VERSION 5.7 ;
  NOWIREEXTENSIONATPIN ON ;
  DIVIDERCHAR "/" ;
  BUSBITCHARS "[]" ;
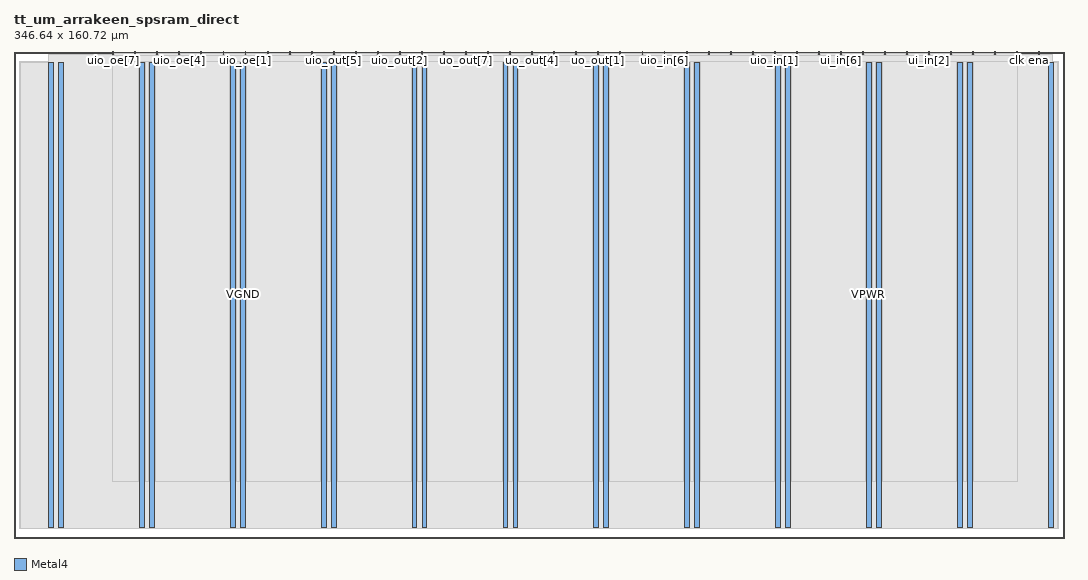
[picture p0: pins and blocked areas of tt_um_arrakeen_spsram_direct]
MACRO tt_um_arrakeen_spsram_direct
  CLASS BLOCK ;
  FOREIGN tt_um_arrakeen_spsram_direct ;
  ORIGIN 0.000 0.000 ;
  SIZE 346.640 BY 160.720 ;
  PIN VGND
    DIRECTION INOUT ;
    USE GROUND ;
    PORT
      LAYER Metal4 ;
        RECT 14.740 3.620 16.340 157.100 ;
    END
    PORT
      LAYER Metal4 ;
        RECT 44.740 3.620 46.340 157.100 ;
    END
    PORT
      LAYER Metal4 ;
        RECT 74.740 3.620 76.340 157.100 ;
    END
    PORT
      LAYER Metal4 ;
        RECT 104.740 3.620 106.340 157.100 ;
    END
    PORT
      LAYER Metal4 ;
        RECT 134.740 3.620 136.340 157.100 ;
    END
    PORT
      LAYER Metal4 ;
        RECT 164.740 3.620 166.340 157.100 ;
    END
    PORT
      LAYER Metal4 ;
        RECT 194.740 3.620 196.340 157.100 ;
    END
    PORT
      LAYER Metal4 ;
        RECT 224.740 3.620 226.340 157.100 ;
    END
    PORT
      LAYER Metal4 ;
        RECT 254.740 3.620 256.340 157.100 ;
    END
    PORT
      LAYER Metal4 ;
        RECT 284.740 3.620 286.340 157.100 ;
    END
    PORT
      LAYER Metal4 ;
        RECT 314.740 3.620 316.340 157.100 ;
    END
  END VGND
  PIN VPWR
    DIRECTION INOUT ;
    USE POWER ;
    PORT
      LAYER Metal4 ;
        RECT 11.440 3.620 13.040 157.100 ;
    END
    PORT
      LAYER Metal4 ;
        RECT 41.440 3.620 43.040 157.100 ;
    END
    PORT
      LAYER Metal4 ;
        RECT 71.440 3.620 73.040 157.100 ;
    END
    PORT
      LAYER Metal4 ;
        RECT 101.440 3.620 103.040 157.100 ;
    END
    PORT
      LAYER Metal4 ;
        RECT 131.440 3.620 133.040 157.100 ;
    END
    PORT
      LAYER Metal4 ;
        RECT 161.440 3.620 163.040 157.100 ;
    END
    PORT
      LAYER Metal4 ;
        RECT 191.440 3.620 193.040 157.100 ;
    END
    PORT
      LAYER Metal4 ;
        RECT 221.440 3.620 223.040 157.100 ;
    END
    PORT
      LAYER Metal4 ;
        RECT 251.440 3.620 253.040 157.100 ;
    END
    PORT
      LAYER Metal4 ;
        RECT 281.440 3.620 283.040 157.100 ;
    END
    PORT
      LAYER Metal4 ;
        RECT 311.440 3.620 313.040 157.100 ;
    END
    PORT
      LAYER Metal4 ;
        RECT 341.440 3.620 343.040 157.100 ;
    END
  END VPWR
  PIN clk
    DIRECTION INPUT ;
    USE SIGNAL ;
    ANTENNAGATEAREA 1.971200 ;
    ANTENNADIFFAREA 0.410400 ;
    PORT
      LAYER Metal4 ;
        RECT 331.090 159.720 331.390 160.720 ;
    END
  END clk
  PIN ena
    DIRECTION INPUT ;
    USE SIGNAL ;
    PORT
      LAYER Metal4 ;
        RECT 338.370 159.720 338.670 160.720 ;
    END
  END ena
  PIN rst_n
    DIRECTION INPUT ;
    USE SIGNAL ;
    PORT
      LAYER Metal4 ;
        RECT 323.810 159.720 324.110 160.720 ;
    END
  END rst_n
  PIN ui_in[0]
    DIRECTION INPUT ;
    USE SIGNAL ;
    ANTENNAGATEAREA 0.638400 ;
    ANTENNADIFFAREA 0.410400 ;
    PORT
      LAYER Metal4 ;
        RECT 316.530 159.720 316.830 160.720 ;
    END
  END ui_in[0]
  PIN ui_in[1]
    DIRECTION INPUT ;
    USE SIGNAL ;
    ANTENNAGATEAREA 0.638400 ;
    ANTENNADIFFAREA 0.410400 ;
    PORT
      LAYER Metal4 ;
        RECT 309.250 159.720 309.550 160.720 ;
    END
  END ui_in[1]
  PIN ui_in[2]
    DIRECTION INPUT ;
    USE SIGNAL ;
    ANTENNAGATEAREA 0.638400 ;
    ANTENNADIFFAREA 0.410400 ;
    PORT
      LAYER Metal4 ;
        RECT 301.970 159.720 302.270 160.720 ;
    END
  END ui_in[2]
  PIN ui_in[3]
    DIRECTION INPUT ;
    USE SIGNAL ;
    ANTENNAGATEAREA 0.638400 ;
    ANTENNADIFFAREA 0.410400 ;
    PORT
      LAYER Metal4 ;
        RECT 294.690 159.720 294.990 160.720 ;
    END
  END ui_in[3]
  PIN ui_in[4]
    DIRECTION INPUT ;
    USE SIGNAL ;
    ANTENNAGATEAREA 0.638400 ;
    ANTENNADIFFAREA 0.410400 ;
    PORT
      LAYER Metal4 ;
        RECT 287.410 159.720 287.710 160.720 ;
    END
  END ui_in[4]
  PIN ui_in[5]
    DIRECTION INPUT ;
    USE SIGNAL ;
    ANTENNAGATEAREA 0.638400 ;
    ANTENNADIFFAREA 0.410400 ;
    PORT
      LAYER Metal4 ;
        RECT 280.130 159.720 280.430 160.720 ;
    END
  END ui_in[5]
  PIN ui_in[6]
    DIRECTION INPUT ;
    USE SIGNAL ;
    ANTENNAGATEAREA 0.638400 ;
    ANTENNADIFFAREA 0.410400 ;
    PORT
      LAYER Metal4 ;
        RECT 272.850 159.720 273.150 160.720 ;
    END
  END ui_in[6]
  PIN ui_in[7]
    DIRECTION INPUT ;
    USE SIGNAL ;
    ANTENNAGATEAREA 0.492800 ;
    ANTENNADIFFAREA 0.410400 ;
    PORT
      LAYER Metal4 ;
        RECT 265.570 159.720 265.870 160.720 ;
    END
  END ui_in[7]
  PIN uio_in[0]
    DIRECTION INPUT ;
    USE SIGNAL ;
    ANTENNAGATEAREA 0.492800 ;
    ANTENNADIFFAREA 0.410400 ;
    PORT
      LAYER Metal4 ;
        RECT 258.290 159.720 258.590 160.720 ;
    END
  END uio_in[0]
  PIN uio_in[1]
    DIRECTION INPUT ;
    USE SIGNAL ;
    ANTENNAGATEAREA 0.492800 ;
    ANTENNADIFFAREA 0.410400 ;
    PORT
      LAYER Metal4 ;
        RECT 251.010 159.720 251.310 160.720 ;
    END
  END uio_in[1]
  PIN uio_in[2]
    DIRECTION INPUT ;
    USE SIGNAL ;
    ANTENNAGATEAREA 0.492800 ;
    ANTENNADIFFAREA 0.410400 ;
    PORT
      LAYER Metal4 ;
        RECT 243.730 159.720 244.030 160.720 ;
    END
  END uio_in[2]
  PIN uio_in[3]
    DIRECTION INPUT ;
    USE SIGNAL ;
    ANTENNAGATEAREA 0.492800 ;
    ANTENNADIFFAREA 0.410400 ;
    PORT
      LAYER Metal4 ;
        RECT 236.450 159.720 236.750 160.720 ;
    END
  END uio_in[3]
  PIN uio_in[4]
    DIRECTION INPUT ;
    USE SIGNAL ;
    ANTENNAGATEAREA 0.492800 ;
    ANTENNADIFFAREA 0.410400 ;
    PORT
      LAYER Metal4 ;
        RECT 229.170 159.720 229.470 160.720 ;
    END
  END uio_in[4]
  PIN uio_in[5]
    DIRECTION INPUT ;
    USE SIGNAL ;
    ANTENNAGATEAREA 0.492800 ;
    ANTENNADIFFAREA 0.410400 ;
    PORT
      LAYER Metal4 ;
        RECT 221.890 159.720 222.190 160.720 ;
    END
  END uio_in[5]
  PIN uio_in[6]
    DIRECTION INPUT ;
    USE SIGNAL ;
    ANTENNAGATEAREA 0.492800 ;
    ANTENNADIFFAREA 0.410400 ;
    PORT
      LAYER Metal4 ;
        RECT 214.610 159.720 214.910 160.720 ;
    END
  END uio_in[6]
  PIN uio_in[7]
    DIRECTION INPUT ;
    USE SIGNAL ;
    ANTENNAGATEAREA 0.492800 ;
    ANTENNADIFFAREA 0.410400 ;
    PORT
      LAYER Metal4 ;
        RECT 207.330 159.720 207.630 160.720 ;
    END
  END uio_in[7]
  PIN uio_oe[0]
    DIRECTION OUTPUT ;
    USE SIGNAL ;
    ANTENNADIFFAREA 0.360800 ;
    PORT
      LAYER Metal4 ;
        RECT 83.570 159.720 83.870 160.720 ;
    END
  END uio_oe[0]
  PIN uio_oe[1]
    DIRECTION OUTPUT ;
    USE SIGNAL ;
    ANTENNADIFFAREA 0.360800 ;
    PORT
      LAYER Metal4 ;
        RECT 76.290 159.720 76.590 160.720 ;
    END
  END uio_oe[1]
  PIN uio_oe[2]
    DIRECTION OUTPUT ;
    USE SIGNAL ;
    ANTENNADIFFAREA 0.360800 ;
    PORT
      LAYER Metal4 ;
        RECT 69.010 159.720 69.310 160.720 ;
    END
  END uio_oe[2]
  PIN uio_oe[3]
    DIRECTION OUTPUT ;
    USE SIGNAL ;
    ANTENNADIFFAREA 0.360800 ;
    PORT
      LAYER Metal4 ;
        RECT 61.730 159.720 62.030 160.720 ;
    END
  END uio_oe[3]
  PIN uio_oe[4]
    DIRECTION OUTPUT ;
    USE SIGNAL ;
    ANTENNADIFFAREA 0.360800 ;
    PORT
      LAYER Metal4 ;
        RECT 54.450 159.720 54.750 160.720 ;
    END
  END uio_oe[4]
  PIN uio_oe[5]
    DIRECTION OUTPUT ;
    USE SIGNAL ;
    ANTENNADIFFAREA 0.360800 ;
    PORT
      LAYER Metal4 ;
        RECT 47.170 159.720 47.470 160.720 ;
    END
  END uio_oe[5]
  PIN uio_oe[6]
    DIRECTION OUTPUT ;
    USE SIGNAL ;
    ANTENNADIFFAREA 0.360800 ;
    PORT
      LAYER Metal4 ;
        RECT 39.890 159.720 40.190 160.720 ;
    END
  END uio_oe[6]
  PIN uio_oe[7]
    DIRECTION OUTPUT ;
    USE SIGNAL ;
    ANTENNADIFFAREA 0.360800 ;
    PORT
      LAYER Metal4 ;
        RECT 32.610 159.720 32.910 160.720 ;
    END
  END uio_oe[7]
  PIN uio_out[0]
    DIRECTION OUTPUT ;
    USE SIGNAL ;
    ANTENNADIFFAREA 0.360800 ;
    PORT
      LAYER Metal4 ;
        RECT 141.810 159.720 142.110 160.720 ;
    END
  END uio_out[0]
  PIN uio_out[1]
    DIRECTION OUTPUT ;
    USE SIGNAL ;
    ANTENNADIFFAREA 0.360800 ;
    PORT
      LAYER Metal4 ;
        RECT 134.530 159.720 134.830 160.720 ;
    END
  END uio_out[1]
  PIN uio_out[2]
    DIRECTION OUTPUT ;
    USE SIGNAL ;
    ANTENNADIFFAREA 0.360800 ;
    PORT
      LAYER Metal4 ;
        RECT 127.250 159.720 127.550 160.720 ;
    END
  END uio_out[2]
  PIN uio_out[3]
    DIRECTION OUTPUT ;
    USE SIGNAL ;
    ANTENNADIFFAREA 0.360800 ;
    PORT
      LAYER Metal4 ;
        RECT 119.970 159.720 120.270 160.720 ;
    END
  END uio_out[3]
  PIN uio_out[4]
    DIRECTION OUTPUT ;
    USE SIGNAL ;
    ANTENNADIFFAREA 0.360800 ;
    PORT
      LAYER Metal4 ;
        RECT 112.690 159.720 112.990 160.720 ;
    END
  END uio_out[4]
  PIN uio_out[5]
    DIRECTION OUTPUT ;
    USE SIGNAL ;
    ANTENNADIFFAREA 0.360800 ;
    PORT
      LAYER Metal4 ;
        RECT 105.410 159.720 105.710 160.720 ;
    END
  END uio_out[5]
  PIN uio_out[6]
    DIRECTION OUTPUT ;
    USE SIGNAL ;
    ANTENNADIFFAREA 0.360800 ;
    PORT
      LAYER Metal4 ;
        RECT 98.130 159.720 98.430 160.720 ;
    END
  END uio_out[6]
  PIN uio_out[7]
    DIRECTION OUTPUT ;
    USE SIGNAL ;
    ANTENNADIFFAREA 0.360800 ;
    PORT
      LAYER Metal4 ;
        RECT 90.850 159.720 91.150 160.720 ;
    END
  END uio_out[7]
  PIN uo_out[0]
    DIRECTION OUTPUT ;
    USE SIGNAL ;
    ANTENNADIFFAREA 0.897600 ;
    PORT
      LAYER Metal4 ;
        RECT 200.050 159.720 200.350 160.720 ;
    END
  END uo_out[0]
  PIN uo_out[1]
    DIRECTION OUTPUT ;
    USE SIGNAL ;
    ANTENNADIFFAREA 0.897600 ;
    PORT
      LAYER Metal4 ;
        RECT 192.770 159.720 193.070 160.720 ;
    END
  END uo_out[1]
  PIN uo_out[2]
    DIRECTION OUTPUT ;
    USE SIGNAL ;
    ANTENNADIFFAREA 0.897600 ;
    PORT
      LAYER Metal4 ;
        RECT 185.490 159.720 185.790 160.720 ;
    END
  END uo_out[2]
  PIN uo_out[3]
    DIRECTION OUTPUT ;
    USE SIGNAL ;
    ANTENNADIFFAREA 0.897600 ;
    PORT
      LAYER Metal4 ;
        RECT 178.210 159.720 178.510 160.720 ;
    END
  END uo_out[3]
  PIN uo_out[4]
    DIRECTION OUTPUT ;
    USE SIGNAL ;
    ANTENNADIFFAREA 0.897600 ;
    PORT
      LAYER Metal4 ;
        RECT 170.930 159.720 171.230 160.720 ;
    END
  END uo_out[4]
  PIN uo_out[5]
    DIRECTION OUTPUT ;
    USE SIGNAL ;
    ANTENNADIFFAREA 0.897600 ;
    PORT
      LAYER Metal4 ;
        RECT 163.650 159.720 163.950 160.720 ;
    END
  END uo_out[5]
  PIN uo_out[6]
    DIRECTION OUTPUT ;
    USE SIGNAL ;
    ANTENNADIFFAREA 0.897600 ;
    PORT
      LAYER Metal4 ;
        RECT 156.370 159.720 156.670 160.720 ;
    END
  END uo_out[6]
  PIN uo_out[7]
    DIRECTION OUTPUT ;
    USE SIGNAL ;
    ANTENNADIFFAREA 0.897600 ;
    PORT
      LAYER Metal4 ;
        RECT 149.090 159.720 149.390 160.720 ;
    END
  END uo_out[7]
  OBS
      LAYER Nwell ;
        RECT 1.810 154.640 344.830 157.230 ;
      LAYER Pwell ;
        RECT 1.810 151.120 344.830 154.640 ;
      LAYER Nwell ;
        RECT 1.810 146.800 344.830 151.120 ;
      LAYER Pwell ;
        RECT 1.810 143.280 344.830 146.800 ;
      LAYER Nwell ;
        RECT 1.810 138.960 344.830 143.280 ;
      LAYER Pwell ;
        RECT 1.810 135.440 344.830 138.960 ;
      LAYER Nwell ;
        RECT 1.810 131.120 344.830 135.440 ;
      LAYER Pwell ;
        RECT 1.810 127.600 344.830 131.120 ;
      LAYER Nwell ;
        RECT 1.810 123.280 344.830 127.600 ;
      LAYER Pwell ;
        RECT 1.810 119.760 344.830 123.280 ;
      LAYER Nwell ;
        RECT 1.810 115.440 344.830 119.760 ;
      LAYER Pwell ;
        RECT 1.810 111.920 344.830 115.440 ;
      LAYER Nwell ;
        RECT 1.810 107.600 344.830 111.920 ;
      LAYER Pwell ;
        RECT 1.810 104.080 344.830 107.600 ;
      LAYER Nwell ;
        RECT 1.810 99.760 344.830 104.080 ;
      LAYER Pwell ;
        RECT 1.810 96.240 344.830 99.760 ;
      LAYER Nwell ;
        RECT 1.810 91.920 344.830 96.240 ;
      LAYER Pwell ;
        RECT 1.810 89.730 344.830 91.920 ;
        RECT 1.810 88.400 55.870 89.730 ;
      LAYER Nwell ;
        RECT 55.870 88.400 344.830 89.730 ;
        RECT 1.810 84.080 344.830 88.400 ;
      LAYER Pwell ;
        RECT 1.810 80.560 55.870 84.080 ;
      LAYER Nwell ;
        RECT 55.870 80.560 344.830 84.080 ;
        RECT 1.810 76.240 344.830 80.560 ;
      LAYER Pwell ;
        RECT 1.810 72.720 55.870 76.240 ;
      LAYER Nwell ;
        RECT 55.870 72.720 344.830 76.240 ;
        RECT 1.810 68.400 344.830 72.720 ;
      LAYER Pwell ;
        RECT 1.810 64.880 55.870 68.400 ;
      LAYER Nwell ;
        RECT 55.870 64.880 344.830 68.400 ;
        RECT 1.810 60.560 344.830 64.880 ;
      LAYER Pwell ;
        RECT 1.810 57.040 55.870 60.560 ;
      LAYER Nwell ;
        RECT 55.870 57.040 344.830 60.560 ;
        RECT 1.810 52.720 344.830 57.040 ;
      LAYER Pwell ;
        RECT 1.810 49.200 55.870 52.720 ;
      LAYER Nwell ;
        RECT 55.870 49.200 344.830 52.720 ;
        RECT 1.810 44.880 344.830 49.200 ;
      LAYER Pwell ;
        RECT 1.810 41.360 55.870 44.880 ;
      LAYER Nwell ;
        RECT 55.870 41.360 344.830 44.880 ;
        RECT 1.810 37.040 344.830 41.360 ;
      LAYER Pwell ;
        RECT 1.810 33.520 55.870 37.040 ;
      LAYER Nwell ;
        RECT 55.870 33.520 344.830 37.040 ;
        RECT 1.810 29.200 344.830 33.520 ;
      LAYER Pwell ;
        RECT 1.810 25.680 55.870 29.200 ;
      LAYER Nwell ;
        RECT 55.870 25.680 344.830 29.200 ;
        RECT 1.810 21.360 344.830 25.680 ;
      LAYER Pwell ;
        RECT 1.810 17.840 55.870 21.360 ;
      LAYER Nwell ;
        RECT 55.870 17.840 344.830 21.360 ;
        RECT 1.810 13.520 344.830 17.840 ;
      LAYER Pwell ;
        RECT 1.810 10.000 55.870 13.520 ;
      LAYER Nwell ;
        RECT 55.870 10.000 344.830 13.520 ;
        RECT 1.810 5.680 344.830 10.000 ;
      LAYER Pwell ;
        RECT 1.810 3.490 55.870 5.680 ;
      LAYER Nwell ;
        RECT 55.870 3.490 344.830 5.680 ;
        RECT 1.810 3.000 344.830 3.490 ;
      LAYER Metal1 ;
        RECT 2.240 3.000 344.400 157.100 ;
      LAYER Metal2 ;
        RECT 11.580 3.000 342.900 157.830 ;
      LAYER Metal3 ;
        RECT 11.530 3.000 342.950 159.460 ;
      LAYER Metal4 ;
        RECT 33.210 159.420 39.590 159.890 ;
        RECT 40.490 159.420 46.870 159.890 ;
        RECT 47.770 159.420 54.150 159.890 ;
        RECT 55.050 159.420 61.430 159.890 ;
        RECT 62.330 159.420 68.710 159.890 ;
        RECT 69.610 159.420 75.990 159.890 ;
        RECT 76.890 159.420 83.270 159.890 ;
        RECT 84.170 159.420 90.550 159.890 ;
        RECT 91.450 159.420 97.830 159.890 ;
        RECT 98.730 159.420 105.110 159.890 ;
        RECT 106.010 159.420 112.390 159.890 ;
        RECT 113.290 159.420 119.670 159.890 ;
        RECT 120.570 159.420 126.950 159.890 ;
        RECT 127.850 159.420 134.230 159.890 ;
        RECT 135.130 159.420 141.510 159.890 ;
        RECT 142.410 159.420 148.790 159.890 ;
        RECT 149.690 159.420 156.070 159.890 ;
        RECT 156.970 159.420 163.350 159.890 ;
        RECT 164.250 159.420 170.630 159.890 ;
        RECT 171.530 159.420 177.910 159.890 ;
        RECT 178.810 159.420 185.190 159.890 ;
        RECT 186.090 159.420 192.470 159.890 ;
        RECT 193.370 159.420 199.750 159.890 ;
        RECT 200.650 159.420 207.030 159.890 ;
        RECT 207.930 159.420 214.310 159.890 ;
        RECT 215.210 159.420 221.590 159.890 ;
        RECT 222.490 159.420 228.870 159.890 ;
        RECT 229.770 159.420 236.150 159.890 ;
        RECT 237.050 159.420 243.430 159.890 ;
        RECT 244.330 159.420 250.710 159.890 ;
        RECT 251.610 159.420 257.990 159.890 ;
        RECT 258.890 159.420 265.270 159.890 ;
        RECT 266.170 159.420 272.550 159.890 ;
        RECT 273.450 159.420 279.830 159.890 ;
        RECT 280.730 159.420 287.110 159.890 ;
        RECT 288.010 159.420 294.390 159.890 ;
        RECT 295.290 159.420 301.670 159.890 ;
        RECT 302.570 159.420 308.950 159.890 ;
        RECT 309.850 159.420 316.230 159.890 ;
        RECT 317.130 159.420 323.510 159.890 ;
        RECT 324.410 159.420 330.790 159.890 ;
        RECT 32.620 157.400 331.380 159.420 ;
        RECT 32.620 18.570 41.140 157.400 ;
        RECT 43.340 18.570 44.440 157.400 ;
        RECT 46.640 18.570 71.140 157.400 ;
        RECT 73.340 18.570 74.440 157.400 ;
        RECT 76.640 18.570 101.140 157.400 ;
        RECT 103.340 18.570 104.440 157.400 ;
        RECT 106.640 18.570 131.140 157.400 ;
        RECT 133.340 18.570 134.440 157.400 ;
        RECT 136.640 18.570 161.140 157.400 ;
        RECT 163.340 18.570 164.440 157.400 ;
        RECT 166.640 18.570 191.140 157.400 ;
        RECT 193.340 18.570 194.440 157.400 ;
        RECT 196.640 18.570 221.140 157.400 ;
        RECT 223.340 18.570 224.440 157.400 ;
        RECT 226.640 18.570 251.140 157.400 ;
        RECT 253.340 18.570 254.440 157.400 ;
        RECT 256.640 18.570 281.140 157.400 ;
        RECT 283.340 18.570 284.440 157.400 ;
        RECT 286.640 18.570 311.140 157.400 ;
        RECT 313.340 18.570 314.440 157.400 ;
        RECT 316.640 18.570 331.380 157.400 ;
  END
END tt_um_arrakeen_spsram_direct
END LIBRARY

